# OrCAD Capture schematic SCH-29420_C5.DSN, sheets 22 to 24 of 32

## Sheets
22 P20_USB3.x_TYPE_C: size A2
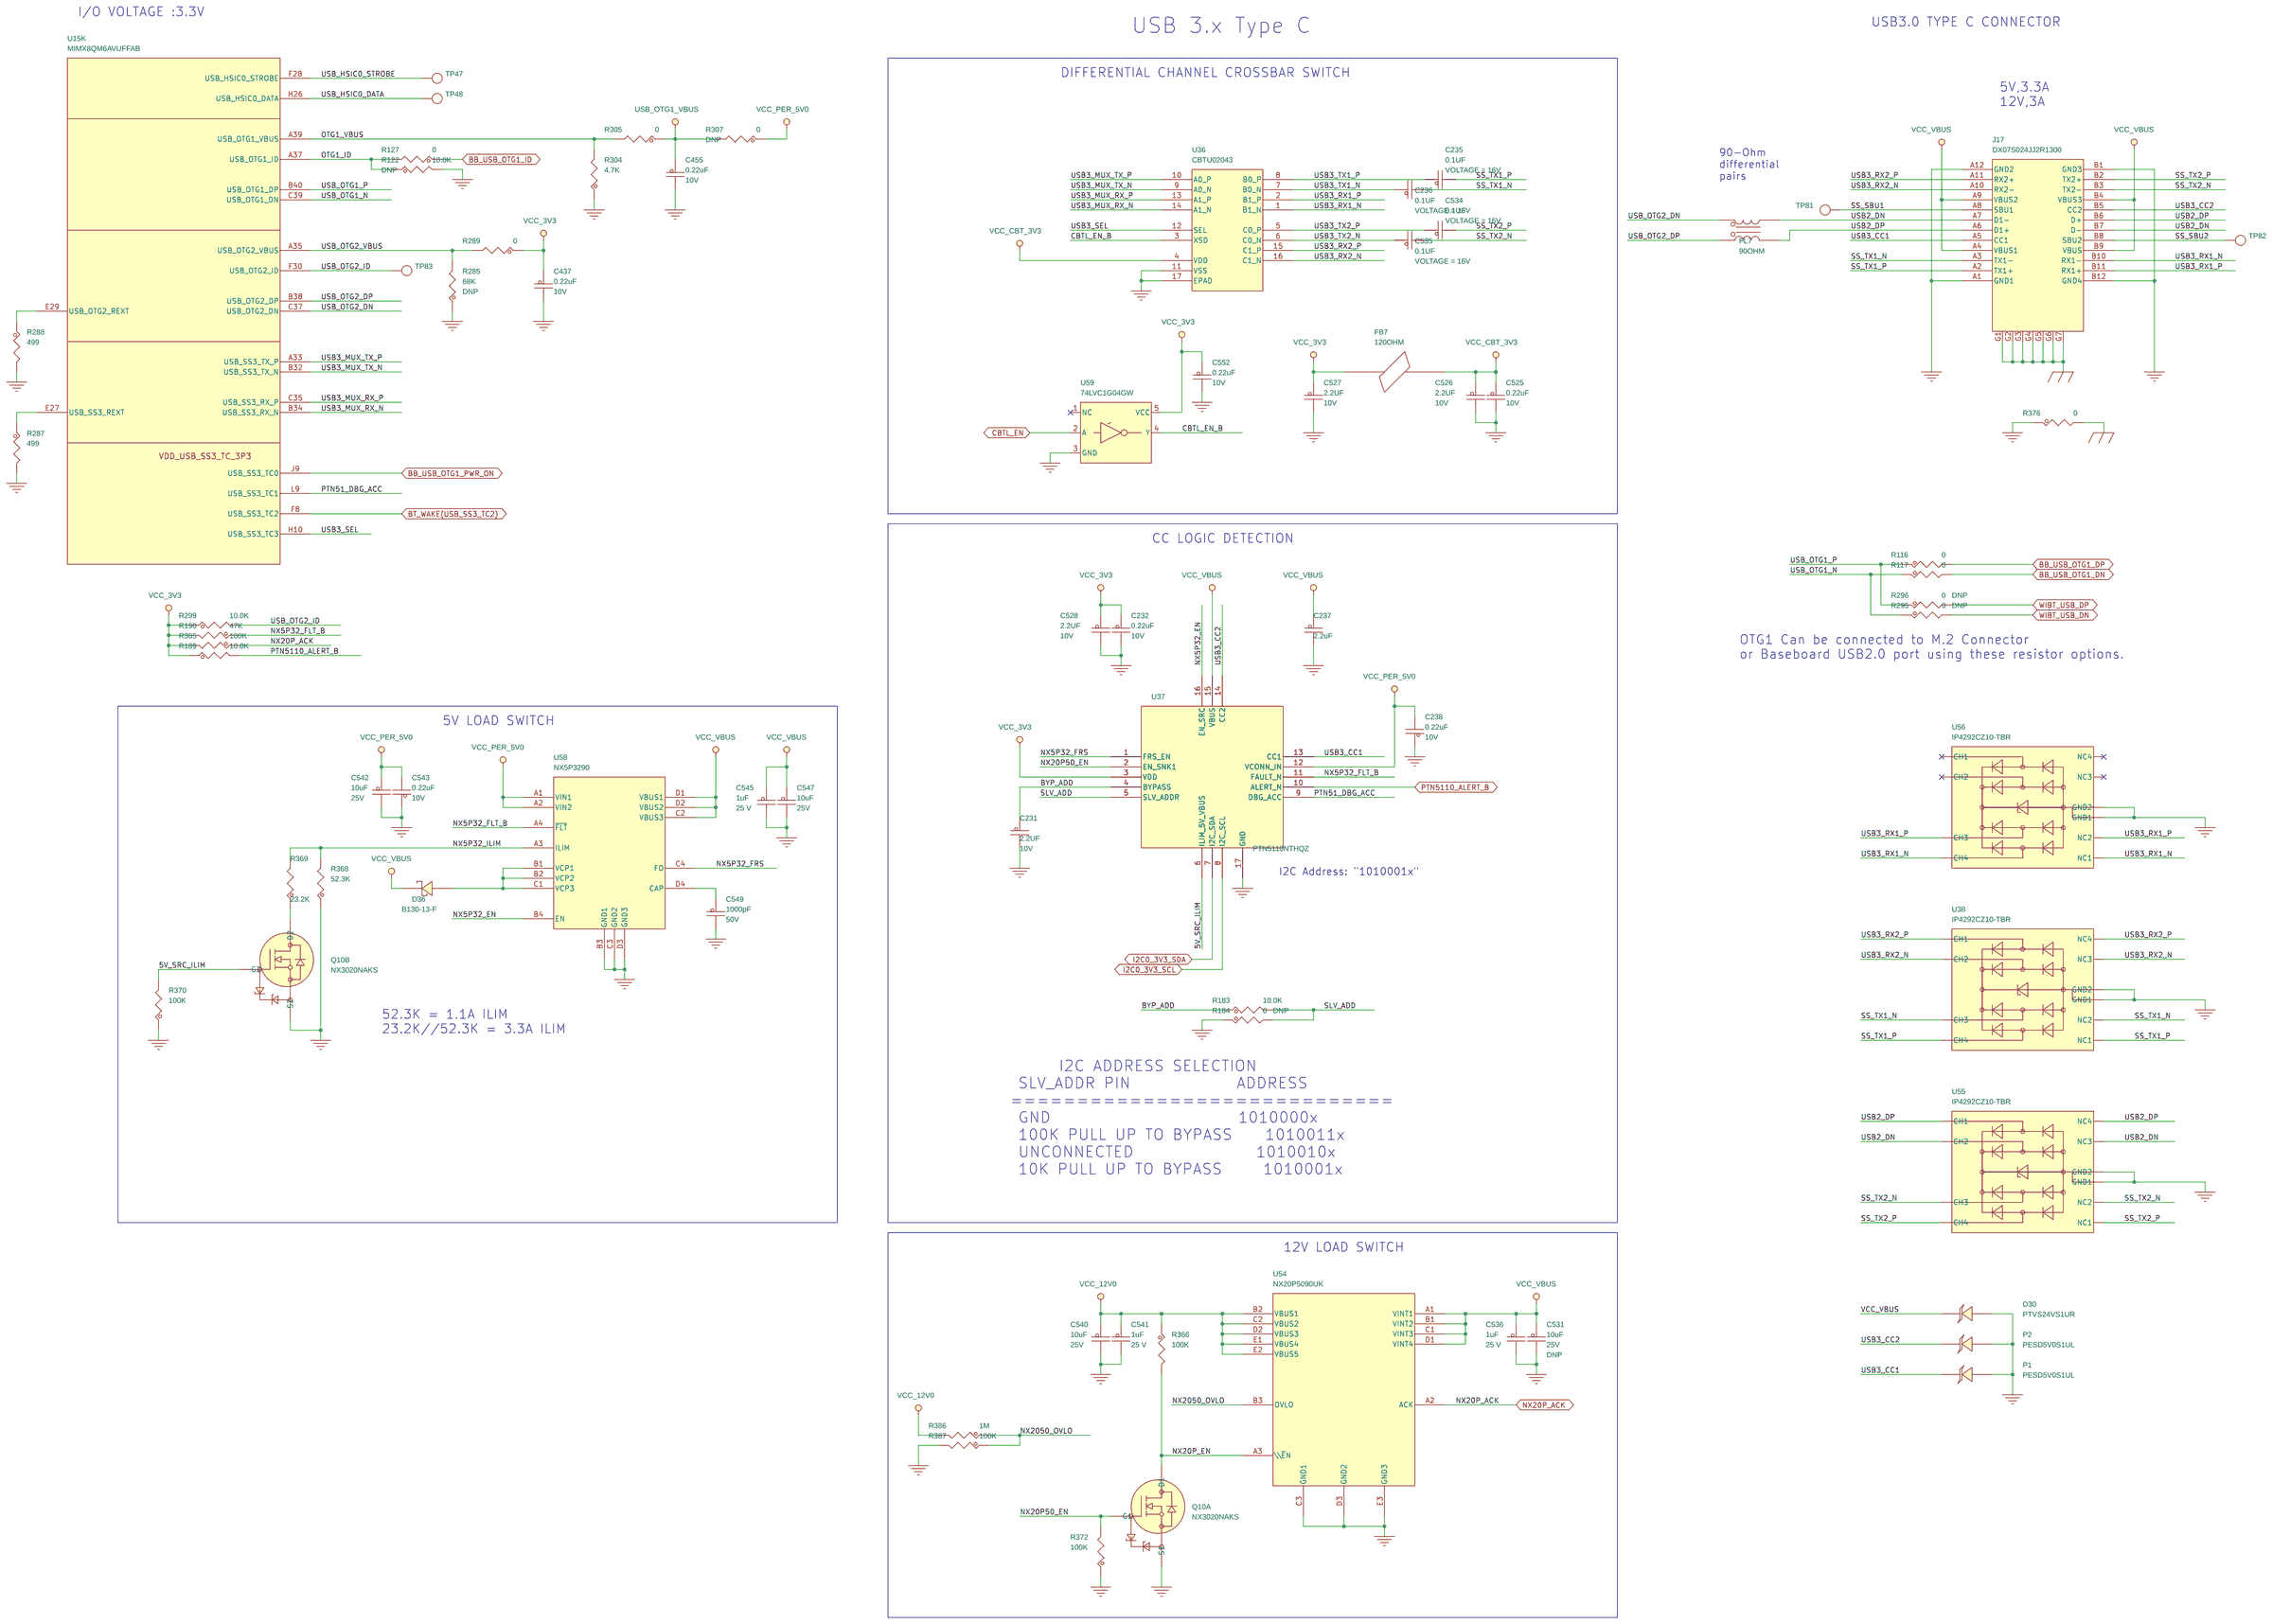
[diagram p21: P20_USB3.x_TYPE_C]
23 P21_PCIe_SATA: size A2
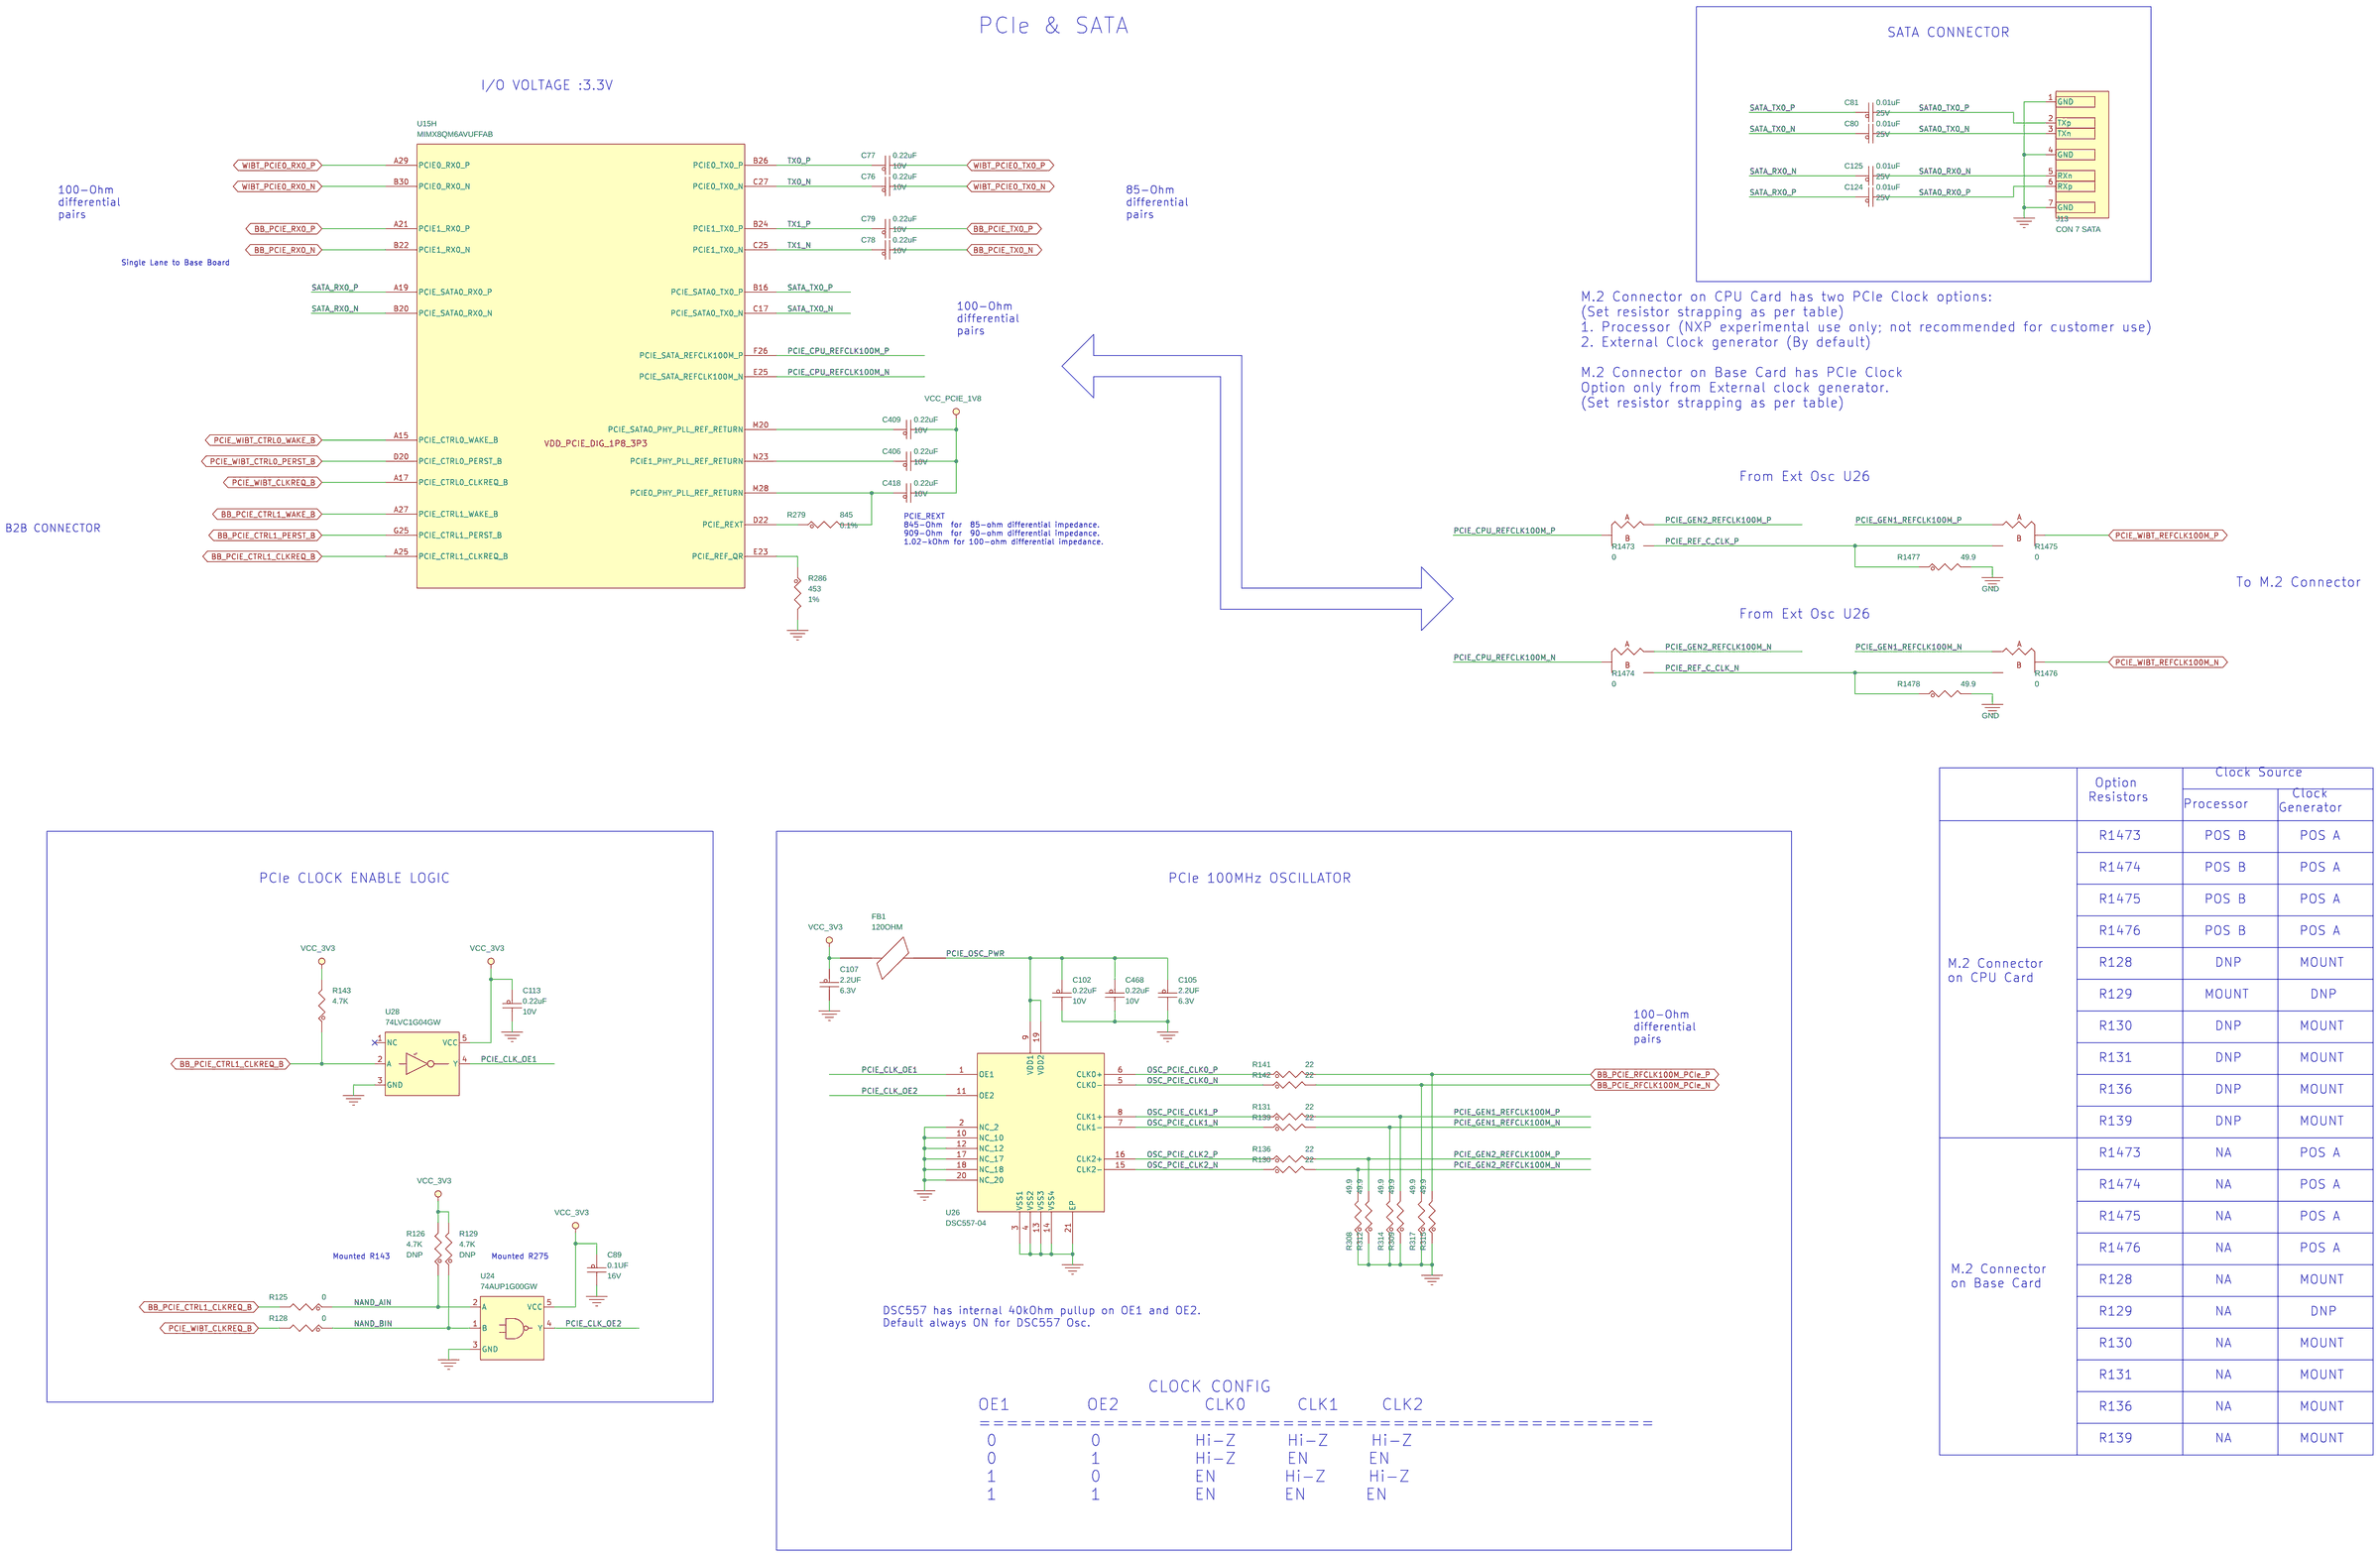
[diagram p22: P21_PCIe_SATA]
24 P23_ETHERNET_PHY: size A2

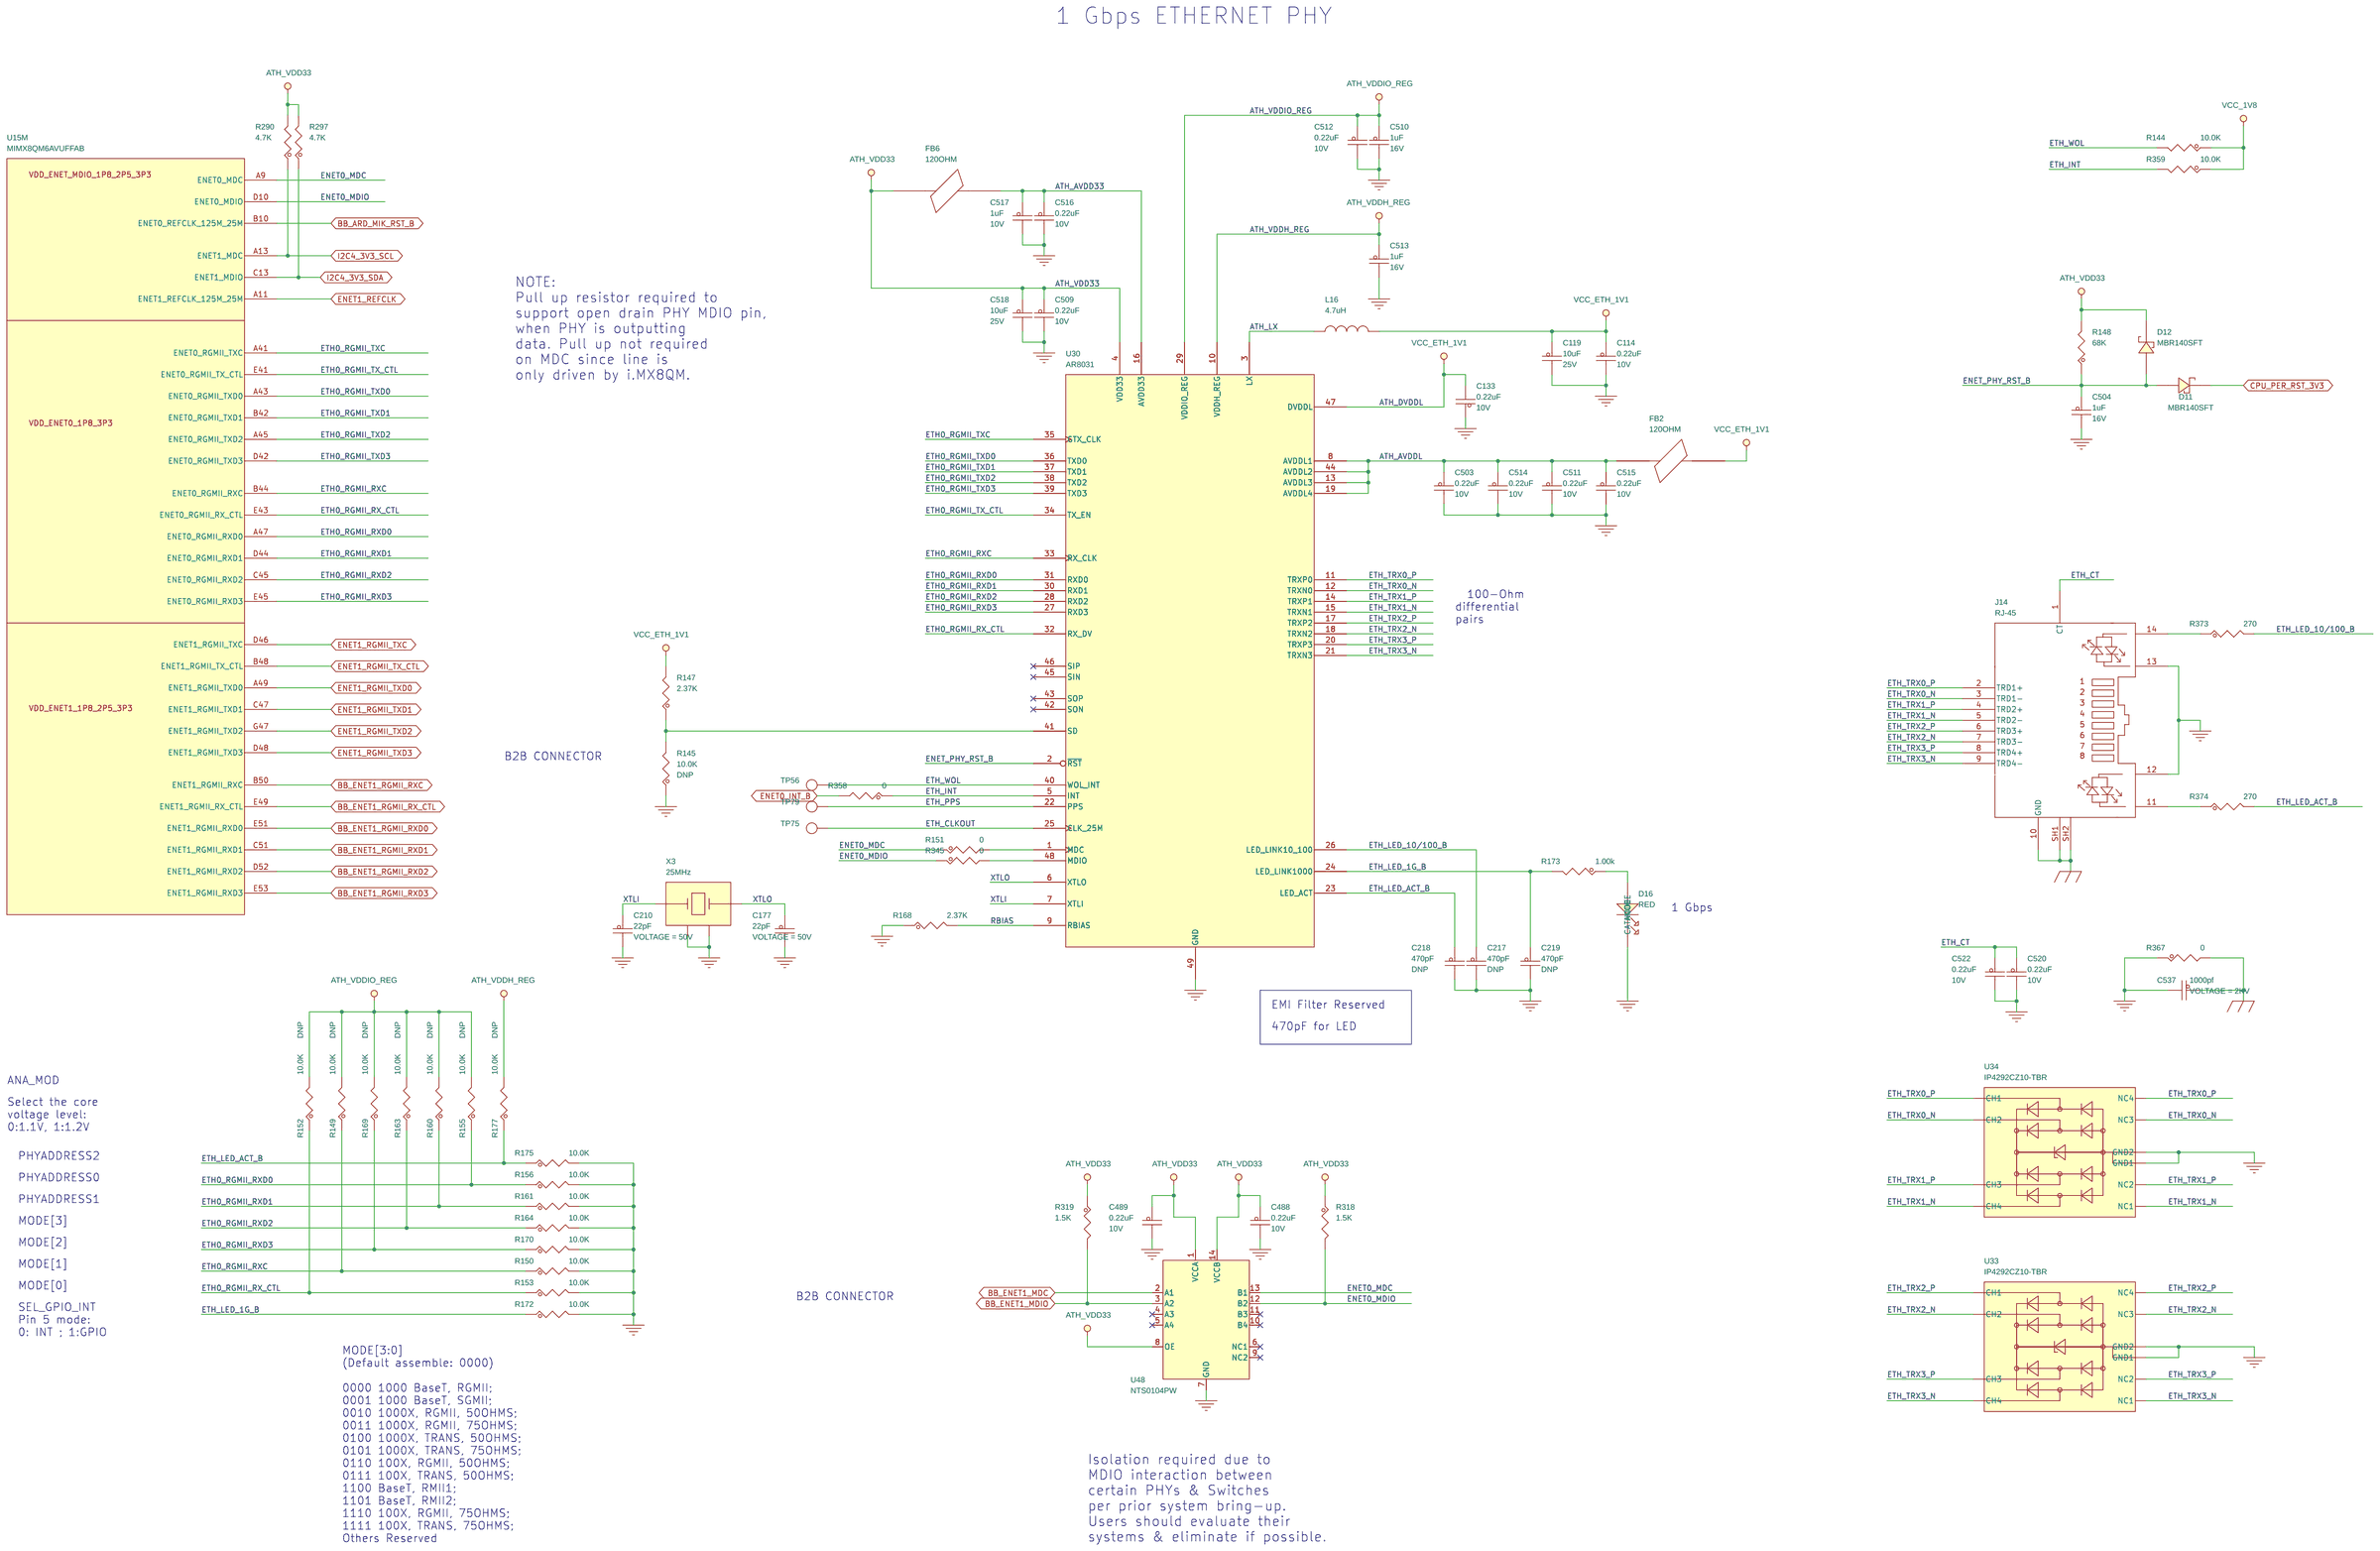
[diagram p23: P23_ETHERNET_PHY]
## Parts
sheet P20_USB3.x_TYPE_C
C231  2.2UF  [CC0402_25]
C232  0.22uF  [CC0402_25]
C235  0.1UF  [CC0402_25]
C236  0.1UF  [CC0402_25]
C237  2.2uF  [CC0603_OV]
C238  0.22uF  [CC0402_25]
C437  0.22uF  [CC0402_25]
C455  0.22uF  [CC0402_25]
C525  0.22uF  [CC0402_25]
C526  2.2UF  [CC0402_25]
C527  2.2UF  [CC0402_25]
C528  2.2UF  [CC0402_25]
C531  10uF  [CC0603_OV]
C534  0.1UF  [CC0402_25]
C535  0.1UF  [CC0402_25]
C536  1uF  [CC0402_25]
C540  10uF  [CC0603_OV]
C541  1uF  [CC0402_25]
C542  10uF  [CC0603_OV]
C543  0.22uF  [CC0402_25]
C545  1uF  [CC0402_25]
C547  10uF  [CC0603_OV]
C549  1000pF  [CC0402_25]
C552  0.22uF  [CC0402_25]
D30  PTVS24VS1UR  [sod123w]
D36  B130-13-F  [sma2_4_4p6x2p9]
FB7  120OHM  [IND_0603]
FL7  90OHM  [ind4_choke_0805]
J17  DX07S024JJ2R1300  [usb24_type_c_dx07S024_sm]
P1  PESD5V0S1UL  [sod-882]
P2  PESD5V0S1UL  [sod-882]
Q10  NX3020NAKS  [sot-363_0p65_smt]  (sections A,B)
R116  0  [RC0402_25]
R117  0  [RC0402_25]
R122  10.0K  [RC0402_25]
R127  0  [RC0402_25]
R183  10.0K  [RC0402_25]
R184  0  [RC0402_25]
R189  10.0K  [RC0402_25]
R190  47K  [RC0402_25]
R285  68K  [RC0402_25]
R287  499  [RC0402_25]
R288  499  [RC0402_25]
R289  0  [RC0402_25]
R295  0  [RC0402_25]
R296  0  [RC0402_25]
R299  10.0K  [RC0402_25]
R304  4.7K  [RC0402_25]
R305  0  [RC0402_25]
R307  0  [RC0402_25]
R365  100K  [RC0402_25]
R366  100K  [RC0402_25]
R368  52.3K  [RC0402_25]
R369  23.2K  [RC0402_25]
R370  100K  [RC0402_25]
R372  100K  [RC0402_25]
R376  0  [RC0402_25]
R386  1M  [RC0402_25]
R387  100K  [RC0402_25]
TP47  TPAD_050  [TPAD_050]
TP48  TPAD_050  [TPAD_050]
TP81  TPAD_050  [TPAD_050]
TP82  TPAD_050  [TPAD_050]
TP83  TPAD_050  [TPAD_050]
U36  CBTU02043  [huqfn16_1p6x2p4]
U37  PTN5110NTHQZ  [hx2qfn16_0p4_2p7x2p7]
U38  IP4292CZ10-TBR  [xson10_0p5_1p1x2p6mm]
U54  NX20P5090UK  [wlcsp15_0p5_1p57x2p59]
U55  IP4292CZ10-TBR  [xson10_0p5_1p1x2p6mm]
U56  IP4292CZ10-TBR  [xson10_0p5_1p1x2p6mm]
U58  NX5P3290  [bga16_0p5_2p15x2p15]
U59  74LVC1G04GW  [sc70-5]
sheet P21_PCIe_SATA
C76  0.22uF  [CC0402_25]
C77  0.22uF  [CC0402_25]
C78  0.22uF  [CC0402_25]
C79  0.22uF  [CC0402_25]
C80  0.01uF  [CC0402_25]
C81  0.01uF  [CC0402_25]
C89  0.1UF  [CC0402_25]
C102  0.22uF  [CC0402_25]
C105  2.2UF  [CC0402_25]
C107  2.2UF  [CC0402_25]
C113  0.22uF  [CC0402_25]
C124  0.01uF  [CC0402_25]
C125  0.01uF  [CC0402_25]
C406  0.22uF  [0402_CC]
C409  0.22uF  [CC0402_25]
C418  0.22uF  [CC0402_25]
C468  0.22uF  [CC0402_25]
FB1  120OHM  [IND_0603]
J13  CON 7 SATA  [con7_sata_th_17x5mm]
R125  0  [RC0402_25]
R126  4.7K  [RC0402_25]
R128  0  [RC0402_25]
R129  4.7K  [RC0402_25]
R130  22  [RC0402_25]
R131  22  [RC0402_25]
R136  22  [RC0402_25]
R139  22  [RC0402_25]
R141  22  [RC0402_25]
R142  22  [RC0402_25]
R143  4.7K  [RC0402_25]
R279  845  [RC0402_25]
R286  453  [RC0402_25]
R308  49.9  [RC0402_25]
R309  49.9  [RC0402_25]
R312  49.9  [RC0402_25]
R314  49.9  [RC0402_25]
R315  49.9  [RC0402_25]
R317  49.9  [RC0402_25]
R1473  0  [RC0402_X2]
R1474  0  [RC0402_X2]
R1475  0  [RC0402_X2]
R1476  0  [RC0402_X2]
R1477  49.9  [RC0402_25]
R1478  49.9  [RC0402_25]
U24  74AUP1G00GW  [sc70-5]
U26  DSC557-04  [qfn20_0p5_5x3mm_ep3p9x2p1]
U28  74LVC1G04GW  [sc70-5]
sheet P23_ETHERNET_PHY
C114  0.22uF  [CC0402_25]
C119  10uF  [CC0603_OV]
C133  0.22uF  [CC0402_25]
C177  22pF  [CC0402_25]
C210  22pF  [CC0402_25]
C217  470pF  [CC0402_25]
C218  470pF  [CC0402_25]
C219  470pF  [CC0402_25]
C488  0.22uF  [CC0402_25]
C489  0.22uF  [CC0402_25]
C503  0.22uF  [CC0402_25]
C504  1uF  [CC0402_25]
C509  0.22uF  [CC0402_25]
C510  1uF  [CC0402_25]
C511  0.22uF  [CC0402_25]
C512  0.22uF  [CC0402_25]
C513  1uF  [CC0402_25]
C514  0.22uF  [CC0402_25]
C515  0.22uF  [CC0402_25]
C516  0.22uF  [CC0402_25]
C517  1uF  [CC0402_25]
C518  10uF  [CC0603_OV]
C520  0.22uF  [CC0402_25]
C522  0.22uF  [CC0402_25]
C537  1000pf  [CC1210]
D11  MBR140SFT  [sod123lf]
D12  MBR140SFT  [sod123lf]
D16  RED  [LED_0603]
FB2  120OHM  [IND_0603]
FB6  120OHM  [IND_0603]
J14  RJ-45  [con_rj45_10_2led_th]
L16  4.7uH  [ind_nr4018_4x4]
R144  10.0K  [RC0402_25]
R145  10.0K  [RC0402_25]
R147  2.37K  [RC0402_25]
R148  68K  [RC0402_25]
R149  10.0K  [RC0402_25]
R150  10.0K  [RC0402_25]
R151  0  [RC0402_25]
R152  10.0K  [RC0402_25]
R153  10.0K  [RC0402_25]
R155  10.0K  [RC0402_25]
R156  10.0K  [RC0402_25]
R160  10.0K  [RC0402_25]
R161  10.0K  [RC0402_25]
R163  10.0K  [RC0402_25]
R164  10.0K  [RC0402_25]
R168  2.37K  [RC0402_25]
R169  10.0K  [RC0402_25]
R170  10.0K  [RC0402_25]
R172  10.0K  [RC0402_25]
R173  1.00k  [RC0402_25]
R175  10.0K  [RC0402_25]
R177  10.0K  [RC0402_25]
R290  4.7K  [RC0402_25]
R297  4.7K  [RC0402_25]
R318  1.5K  [RC0402_25]
R319  1.5K  [RC0402_25]
R345  0  [RC0402_25]
R358  0  [RC0402_25]
R359  10.0K  [RC0402_25]
R367  0  [RC0402_25]
R373  270  [RC0402_25]
R374  270  [RC0402_25]
TP56  TPAD_050  [TPAD_050]
TP75  TPAD_050  [TPAD_050]
TP79  TPAD_050  [TPAD_050]
U15  MIMX8QM6AVUFFAB  [imx8_bga_1313]  (sections A,B,C,D,E,F,G,H,I,J,K,L,M,N,O,P,Q,R,S,T,U)
U30  AR8031  [qfn48_0p4_6x6mm_epad]
U33  IP4292CZ10-TBR  [xson10_0p5_1p1x2p6mm]
U34  IP4292CZ10-TBR  [xson10_0p5_1p1x2p6mm]
U48  NTS0104PW  [tssop14]
X3  25MHz  [xtal4_5p2x3p4mm_sm]

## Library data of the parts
C231 C526-C528 = CAP_NP: CAP CER 2.2UF 10V 10% X5R 0402; AGILE_PN: 150-79475; CAD_APPROVED: Yes; EN: 102-1-00208; FPLIST: CC0402_25,CC0402_HD,0402_CC; HEIGHT: 0.56MM; MFG_NAME01: AVX; MFG_PN01: 0402ZD225KAT2A; ROHS: Yes; TOL: 10%; Tolerance: 10%; VOLTAGE: 10V
C76-C79 C102 C113 C114 C133 C232 C238 C406 C409 C418 C437 C455 C468 C488 C489 C503 C509 C511 C512 C514-C516 C520 C522 C525 C543 C552 = CAP_NP: CAP CER 0.22uF 10V 10% X7R AEC-Q200 0402; AGILE_PN: 150-79031; CAD_APPROVED: Yes; EN: 102-1-01816; FPLIST: CC0402_25,CC0402_HD,0402_CC; HEIGHT: 0.55MM; MFG_NAME01: TDK; MFG_PN01: CGA2B1X7R1A224K050BC; ROHS: Yes; TOL: 10%; Tolerance: 10%; VOLTAGE: 10V
C89 C235 C236 C534 C535 = CAP_NP: CAP CER 0.1UF 16V 10% X7R 0402; AGILE_PN: 150-75182; CAD_APPROVED: Yes; EN: 102-1-01629; FPLIST: CC0402_25,CC0402_HD,0402_CC; HEIGHT: 0.635MM; MFG_NAME01: AVX; MFG_PN01: 0402YC104KAT2A; ROHS: Yes; TOL: 10%; Tolerance: 10%; VOLTAGE: 16V
C237 = CAP_NP: CAP CER 2.2uF 50V 10% X5R 0603; AGILE_PN: 150-79973; CAD_APPROVED: Yes; EN: 102-1-02211; FPLIST: CC0603_OV,CC0603,0603_CC; HEIGHT: 1MM; MFG_NAME01: Taiyo Yuden; MFG_PN01: UMK107BBJ225KA-T; ROHS: Yes; TOL: 10%; Temp_Range: -55 to 85&#8451;; Tolerance: 10%; VOLTAGE: 150V
C531 = CAP_NP: CAP CER 10uF 25V 20% X5R 0603; AGILE_PN: 150-79272; ASSY_OPT: DNP; CAD_APPROVED: Yes; EN: 102-1-01982; FPLIST: CC0603_OV,CC0603,0603_CC; HEIGHT: 1MM; MFG_NAME01: Murata; MFG_PN01: GRM188R61E106MA73D; ROHS: Yes; TOL: 20%; Tolerance: 20%; VOLTAGE: 25V
C536 C541 C545 = CAP_NP: CAP CER 1uF 25V 10% X5R 0402; AGILE_PN: 150-80001; CAD_APPROVED: Yes; EN: 102-1-01993; FPLIST: CC0402_25,CC0402_HD,0402_CC; HEIGHT: 0.55MM; MFG_NAME01: MURATA; MFG_PN01: GRM155R61E105KA12; ROHS: Yes; TOL: 10%; Temp_Range: -55°C to +85°C; Tolerance: 10%; VOLTAGE: 25 V
C119 C518 C540 C542 = CAP_NP: CAP CER 10uF 25V 20% X5R 0603; AGILE_PN: 150-79272; CAD_APPROVED: Yes; EN: 102-1-01982; FPLIST: CC0603_OV,CC0603,0603_CC; HEIGHT: 1MM; MFG_NAME01: Murata; MFG_PN01: GRM188R61E106MA73D; ROHS: Yes; TOL: 20%; Tolerance: 20%; VOLTAGE: 25V
C547 = CAP_NP: CAP CER 10uF 25V 20% X5R 0603; AGILE_PN: 150-79272; ASSY_OPT: NM; CAD_APPROVED: Yes; EN: 102-1-01982; FPLIST: CC0603_OV,CC0603,0603_CC; HEIGHT: 1MM; MFG_NAME01: Murata; MFG_PN01: GRM188R61E106MA73D; ROHS: Yes; TOL: 20%; Tolerance: 20%; VOLTAGE: 25V
C549 = CAP_NP: CAP CER 1000PF 50V X7R 5% 0402; AGILE_PN: 150-75774; CAD_APPROVED: Yes; EN: 102-1-00054; FPLIST: CC0402_25,CC0402_HD,0402_CC; HEIGHT: 0.6MM; MFG_NAME01: CAPAX TECHNOLOGIES INC.; MFG_PN01: 0402X102J500SNT; ROHS: Yes; TOL: 5%; Tolerance: 5%; VOLTAGE: 50V
D30 = DIODE_TVS: DIODE TVS 400W 24V AEC-Q101 SOD123W; AGILE_PN: 480-79613; CAD_APPROVED: Yes; EN: 305-1-00269; HEIGHT: 1.1MM; MFG_NAME01: NEXPERIA; MFG_PN01: PTVS24VS1UR,115; ROHS: Yes
D36 = DIODE_SCHTKY: DIODE SCH RECT 1A 30V SMA; AGILE_PN: 480-79846; CAD_APPROVED: Yes; EN: 106-2-00016; HEIGHT: 2.5MM; MFG_NAME01: Diodes Inc; ROHS: Yes; Temp_Range: -65C to 150C
FB1 FB2 FB6 FB7 = BEAD_FERRITE: IND FER BEAD 120OHM@100MHZ 2A 25% 0603; AGILE_PN: 180-30008; CAD_APPROVED: Yes; EN: 104-1-00022; FPLIST: IND_0603,0603_CC; HEIGHT: 0.95MM; MFG_NAME01: MURATA; MFG_PN01: BLM18PG121SH1; PART_TYPE: FERRITE; ROHS: Yes; TOL: 25%; Tolerance: 25%
FL7 = DLW43: IND CHK 90 OHM@100MHZ 330MA 25% 0805; AGILE_PN: 180-76336; CAD_APPROVED: Yes; EN: 303-0-00024; HEIGHT: 1MM; MFG_NAME01: MURATA; MFG_PN01: DLW21HN900SQ2L; PART_TYPE: CHOKE; ROHS: Yes; TOL: 25%; Tolerance: 25%
J17 = USB_24_TYPE_C: CON 24 USB TYPE_C RA SHLD SMT 0.5MM SP 130H AU; AGILE_PN: 211-79865; CAD_APPROVED: Yes; EN: 201-2-00583; HEIGHT: 3.3MM; MFG_NAME01: JAE; ROHS: Yes
P1 P2 = DIODE_TVS: DIODE TVS UNIDIR 5V AEC-Q101 SOD882; AGILE_PN: 480-79614; CAD_APPROVED: Yes; EN: 305-1-00268; HEIGHT: 0.5MM; MFG_NAME01: NEXPERIA; MFG_PN01: PESD5V0S1UL,315; ROHS: Yes
Q10 = TRAN_DUAL_NMOS_BSS138: TRAN NMOS SW DUAL 180MA 30V 4.5 OHM SOT363; AGILE_PN: 480-79692; CAD_APPROVED: Yes; EN: 107-2-00207; HEIGHT: 1.1 MM; MFG_NAME01: NEXPERIA; MFG_PN01: NX3020NAKS,115; ROHS: Yes
R116 R117 R125 R127 R128 R151 R289 R305 R345 R358 R367 R376 = RES: RES MF ZERO OHM 1/16W -- AEC-Q200 0402; AGILE_PN: 470-80742; CAD_APPROVED: Yes; EN: 101-1-00001; FPLIST: RC0402_25,RC0402_HD,0402_CC; HEIGHT: 0.45 MM; MFG_NAME01: VISHAY INTERTECHNOLOGY; MFG_PN01: CRCW04020000Z0ED; ROHS: Yes
R122 R145 R149 R152 R155 R160 R163 R169 R177 = RES: RES MF 10.0K 1/16W 1% 0402; AGILE_PN: 470-80574; ASSY_OPT: DNP; CAD_APPROVED: Yes; EN: 101-1-00389; FPLIST: RC0402_25,RC0402_HD,0402_CC; HEIGHT: 0.4MM; MFG_NAME01: WALSIN TECHNOLOGY CORP.; MFG_PN01: WR04X1002FTL; ROHS: Yes; TOL: 1%; Tolerance: 1%
R144 R150 R153 R156 R161 R164 R170 R172 R175 R183 R189 R299 R359 = RES: RES MF 10.0K 1/16W 1% 0402; AGILE_PN: 470-80574; CAD_APPROVED: Yes; EN: 101-1-00389; FPLIST: RC0402_25,RC0402_HD,0402_CC; HEIGHT: 0.4MM; MFG_NAME01: WALSIN TECHNOLOGY CORP.; MFG_PN01: WR04X1002FTL; ROHS: Yes; TOL: 1%; Tolerance: 1%
R184 R295 R296 R307 = RES: RES MF ZERO OHM 1/16W -- AEC-Q200 0402; AGILE_PN: 470-80742; ASSY_OPT: DNP; CAD_APPROVED: Yes; EN: 101-1-00001; FPLIST: RC0402_25,RC0402_HD,0402_CC; HEIGHT: 0.45 MM; MFG_NAME01: VISHAY INTERTECHNOLOGY; MFG_PN01: CRCW04020000Z0ED; ROHS: Yes
R190 = RES: RES MF 47K 1/10W 1% AEC-Q200 0402; AGILE_PN: 470-81731; CAD_APPROVED: Yes; EN: 101-1-03402; FPLIST: RC0402_25,RC0402_HD,0402_CC; HEIGHT: 0.40 MM; MFG_NAME01: KOA SPEER; MFG_PN01: RK73H1ETTP4702F; ROHS: Yes; TOL: 1%; Temp_Range: -55C to +155C; Tolerance: 1%
R285 = RES: RES MF 68K 1/16W 5% 0402; AGILE_PN: 470-30330; ASSY_OPT: DNP; CAD_APPROVED: Yes; EN: 101-1-02813; FPLIST: RC0402_25,RC0402_HD,0402_CC; HEIGHT: 0.4MM; MFG_NAME01: TYCO ELECTRONICS; MFG_PN01: CRG0402J68K; ROHS: Yes; TOL: 5%; Tolerance: 5%
R287 R288 = RES: RES MF 499 OHM 1/16W 1% 0402; AGILE_PN: 470-30807; CAD_APPROVED: Yes; EN: 101-1-00264; FPLIST: RC0402_25,RC0402_HD,0402_CC; HEIGHT: 0.40 MM; MFG_NAME01: ROHM; MFG_PN01: MCR01MZPF4990; ROHS: Yes; TOL: 1%; Tolerance: 1%
R143 R290 R297 R304 = RES: RES MF 4.7K 1/16W 5% 0402; AGILE_PN: 470-75626; CAD_APPROVED: Yes; EN: 101-1-02785; FPLIST: RC0402_25,RC0402_HD,0402_CC,RC0402_X2; HEIGHT: 0.41mm; MFG_NAME01: NIC COMPONENTS CORP; MFG_PN01: NRCL04J472TRF; ROHS: Yes; TOL: 5%; Tolerance: 5%
R365 R366 R370 R372 R387 = RES: RES MF 100K 1/16W 5% 0402; AGILE_PN: 470-75597; CAD_APPROVED: Yes; EN: 101-1-02817; FPLIST: RC0402_25,RC0402_HD,0402_CC; HEIGHT: 0.40 MM; MFG_NAME01: VENKEL COMPANY; MFG_PN01: CR0402-16W-104JT; ROHS: Yes; TOL: 5%; Tolerance: 5%
R368 = RES: RES MF 52.3K 1/10W 1% AEC-Q200 0402; AGILE_PN: 470-81734; CAD_APPROVED: Yes; EN: 101-1-00458; FPLIST: RC0402_25,RC0402_HD,0402_CC; HEIGHT: 0.40 MM; MFG_NAME01: KOA SPEER; MFG_PN01: RK73H1ETTP5232F; ROHS: Yes; TOL: 1%; Temp_Range: -55C to +155C; Tolerance: 1%
R369 = RES: RES MF 23.2K 1/10W 1% AEC-Q200 0402; AGILE_PN: 470-30986; CAD_APPROVED: Yes; EN: 101-1-03903; FPLIST: RC0402_25,RC0402_HD,0402_CC; HEIGHT: 0.40 MM; MFG_NAME01: KOA SPEER; MFG_PN01: RK73H1ETTP2322F; ROHS: Yes; Temp_Range: -55C to +155C; Tolerance: 1%
R386 = RES: RES MF 1M 1/16W 1% 0402; AGILE_PN: 470-80575; CAD_APPROVED: Yes; EN: 101-1-00581; FPLIST: RC0402_25,RC0402_HD,0402_CC; HEIGHT: 0.4MM; MFG_NAME01: BOURNS; MFG_PN01: CR0402-FX-1004GLF; ROHS: Yes; TOL: 1%; Tolerance: 1%
TP47 TP48 TP56 TP75 TP79 TP81-TP83 = TESTLOOP: TEST POINT PAD 50MIL DIA SMT, NO PART TO ORDER; AGILE_PN: 211-76644; CAD_APPROVED: Yes; HEIGHT: 0.1MM; MFG_NAME01: NOTACOMPONENT; MFG_PN01: NOTACOMPONENT; ROHS: Yes
U36 = CBTU02043HEJ_17P: IC DIFF MUX/DEMUX 2:1 1.62-3.63V HUQFN16; AGILE_PN: TMP-WF-29679; CAD_APPROVED: Yes; EN: 301-0-01905; HEIGHT: 0.55MM; MFG_NAME01: NXP SEMICONDUCTORS; MFG_PN01: CBTU02043HEJ; PRE_APN: 312-81720; ROHS: Yes
U37 = PTN5110_16P_EP: IC USB PD PHY 1PORT 2.7-5.5V HX2QFN16; AGILE_PN: 315-82772; CAD_APPROVED: YES; EN: 301-0-03045; HEIGHT: 0.4 MM; MFG_NAME01: NXP Semiconductors; ROHS: YES; Temp Range: -40  °C - 85 °C; VOLTAGE: 2.7-5.5V
U33 U34 U38 U55 U56 = PUSB3F96_DFN2510A_10P: DIODE ESD TVS ARRAY USB2 USB3 5.5V 4A DFN2510A-10; AGILE_PN: 480-79837; CAD_APPROVED: Yes; EN: 301-0-01726; HEIGHT: 0.5MM; MFG_NAME01: NEXPERIA; MFG_PN01: IP4292CZ10-TBR,115; ROHS: Yes; Temp_Range: -40C to +85C
U54 = NX20P5090UK: IC USB PWR SW 5A 2.5-20V WLCSP15; AGILE_PN: 315-81116; CAD_APPROVED: Yes; EN: 301-0-01659; HEIGHT: 0.595MM; MFG_NAME01: NXP SEMICONDUCTORS; MFG_PN01: NX20P5090UKAZ; ROHS: Yes
U58 = NX5P3290_16P: IC USB PD SWITCH 4-5.5V WLCSP16; AGILE_PN: 315-81121; CAD_APPROVED: Yes; EN: 301-0-01656; HEIGHT: 0.595MM; MFG_NAME01: NXP SEMICONDUCTORS; MFG_PN01: NX5P3290UKZ; ROHS: Yes
U28 U59 = NC7SZ14: IC INV SGL 1.65-5.5V TSSOP5; AGILE_PN: 315-81077; CAD_APPROVED: Yes; EN: 301-0-01255; HEIGHT: 1.1MM; MFG_NAME01: NEXPERIA; MFG_PN01: 74LVC1G04GW,125; ROHS: Yes
C80 C81 C124 C125 = CAP_NP: CAP CER 0.01UF 25V 10% X7R 0402; AGILE_PN: 150-75183; CAD_APPROVED: Yes; EN: 102-1-00027; FPLIST: CC0402_25,CC0402_HD,0402_CC; HEIGHT: 0.635mm; MFG_NAME01: AVX; MFG_PN01: 04023C103KAT2A; ROHS: Yes; TOL: 10%; Tolerance: 10%; VOLTAGE: 25V
C105 C107 = CAP_NP: CAP CER 2.2UF 6.3V 20% X5R 0402; AGILE_PN: 150-76792; CAD_APPROVED: Yes; EN: 102-1-01843; FPLIST: CC0402_25,CC0402_HD,0402_CC; HEIGHT: 0.55MM; MFG_NAME01: KEMET; MFG_PN01: C0402C225M9PACTU; ROHS: Yes; TOL: 20%; Tolerance: 20%; VOLTAGE: 6.3V
J13 = SATA_PLUG7: CON 1X7 PLUG SATA TH 50MIL SP 335H -- 96L; AGILE_PN: 210-79711; CAD_APPROVED: Yes; EN: 201-1-00982; HEIGHT: 8.527 MM; MFG_NAME01: 3M; MFG_PN01: 5607-5102-SH; ROHS: Yes
R126 R129 = RES: RES MF 4.7K 1/16W 5% 0402; AGILE_PN: 470-75626; ASSY_OPT: DNP; CAD_APPROVED: Yes; EN: 101-1-02785; FPLIST: RC0402_25,RC0402_HD,0402_CC,RC0402_X2; HEIGHT: 0.41mm; MFG_NAME01: NIC COMPONENTS CORP; MFG_PN01: NRCL04J472TRF; ROHS: Yes; TOL: 5%; Tolerance: 5%
R130 R131 R136 R139 R141 R142 = RES: RES MF 22 OHM 1/16W 5% 0402; AGILE_PN: 470-75605; CAD_APPROVED: Yes; EN: 101-1-03406; FPLIST: RC0402_25,RC0402_HD,0402_CC; HEIGHT: 0.4MM; MFG_NAME01: BOURNS; MFG_PN01: CR0402-JW-220GLF; ROHS: Yes; TOL: 5%; Tolerance: 5%
R279 = RES: RES MF 845 OHM 1/16W 0.1% 0402; AGILE_PN: 470-81874; CAD_APPROVED: Yes; EN: 101-1-04012; FPLIST: RC0402_25,RC0402_HD,0402_CC; HEIGHT: 0.35MM; MFG_NAME01: Yageo; MFG_PN01: RT0402BRD07845RL; ROHS: Yes; TOL: 0.1%; Temp_Range: -55C to +155C; Tolerance: 0.1%
R286 = RES: RES MF 453 OHM 1/16W 1% 0402; AGILE_PN: 470-30804; CAD_APPROVED: Yes; EN: 101-1-00260; FPLIST: RC0402_25,RC0402_HD,0402_CC; HEIGHT: 0.40 MM; MFG_NAME01: YAGEO AMERICA; MFG_PN01: RC0402FR-07453RL; ROHS: Yes; TOL: 1%; Tolerance: 1%
R308 R309 R312 R314 R315 R317 = RES: RES MF 49.9 OHM 1/16W 1% 0402; AGILE_PN: 470-75360; CAD_APPROVED: Yes; EN: 101-1-00168; FPLIST: RC0402_25,RC0402_HD,0402_CC; HEIGHT: 0.4MM; MFG_NAME01: BOURNS; MFG_PN01: CR0402-FX-49R9GLF; ROHS: Yes; TOL: 1%; Tolerance: 1%
R1473-R1476 = RES_3PIN: RES MF ZERO OHM 1/16W 5% 0402; AGILE_PN: 470-75394; CAD_APPROVED: Yes; EN: 101-1-04000; FPLIST: RC0402_25,RC0402_HD,RC0402_X2,0402_CC; HEIGHT: 0.45 MM; MFG_NAME01: ROHM; MFG_PN01: MCR01MZPJ000; ROHS: Yes; TOL: 5%; Tolerance: 5%
R1477 R1478 = RES: RES MF 49.9 OHM 1/16W 1% 0402; AGILE_PN: 470-75360; CAD_APPROVED: Yes; EN: 101-1-00168; FPLIST: RC0402_25,RC0402_HD,0402_CC; HEIGHT: 0.4MM; MFG_NAME01: BOURNS; MFG_PN01: CR0402-FX-49R9GLF; ROHS: Yes; TOL: 1%
U24 = 74AUP1G00GW: IC GATE NAND 2IN 0.8-3.6V.TSSOP5; AGILE_PN: 312-81222; CAD_APPROVED: Yes; EN: 301-0-01730; HEIGHT: 1.1MM; MFG_NAME01: NEXPERIA; MFG_PN01: 74AUP1G00GW,125; ROHS: Yes
U26 = DSC557_QFN20_EP: IC PCIe CLK GEN 100MHZ 2.25-3.6V QFN20; AGILE_PN: 312-81849; CAD_APPROVED: Yes; EN: 301-0-01848; HEIGHT: 0.9MM; MFG_NAME01: MICROCHIP TECHNOLOGY INC; MFG_PN01: DSC557-04444KI1; ROHS: Yes
C177 C210 = CAP_NP: CAP CER 22pF 50V 1% C0G 0402; AGILE_PN: 150-79491; CAD_APPROVED: Yes; EN: 102-1-00765; FPLIST: CC0402_25,CC0402_HD,0402_CC; HEIGHT: 0.56MM; MFG_NAME01: AVX; MFG_PN01: 04025A220FAT2A; ROHS: Yes; TOL: 1%; Tolerance: 1%; VOLTAGE: 50V
C217-C219 = CAP_NP: CAP CER 470pF 50V 10% X7R AEC-Q200 0402; AGILE_PN: 150-79233; ASSY_OPT: DNP; CAD_APPROVED: Yes; EN: 102-1-00071; FPLIST: CC0402_25,CC0402_HD,0402_CC; HEIGHT: 0.55MM; MFG_NAME01: Murata; MFG_PN01: GCM155R71H471KA37; ROHS: Yes; TOL: 10%; Tolerance: 10%
C504 C510 C513 = CAP_NP: CAP CER 1uF 16V 10% X5R 0402; AGILE_PN: 150-79794; CAD_APPROVED: Yes; EN: 102-1-01641; FPLIST: CC0402_25,CC0402_HD,0402_CC; HEIGHT: 0.55MM; MFG_NAME01: NIC COMPONENTS CORP; MFG_PN01: NMC0402X5R105K16TRPF; ROHS: Yes; TOL: +/-10%; Tolerance: +/-10%; VOLTAGE: 16V
C517 = CAP_NP: CAP CER 1uF 10V 10% X7S AEC-Q200 0402; AGILE_PN: 150-79497; CAD_APPROVED: Yes; EN: 102-1-02280; FPLIST: CC0402_25,CC0402_HD,0402_CC; HEIGHT: 0.7MM; MFG_NAME01: murata; MFG_PN01: GCM155C71A105KE38D; ROHS: Yes; TOL: 10%; Tolerance: 10%; VOLTAGE: 10V
C537 = CAP_NP: CAP CER 1000PF 2KV 10% X7R 1210; AGILE_PN: 150-75027; CAD_APPROVED: Yes; EN: 102-1-01612; FPLIST: CC1210,1210_CC; HEIGHT: 1.7MM; MFG_NAME01: AVX; MFG_PN01: 1210GC102KAT1A; ROHS: Yes; TOL: 10%; Tolerance: 10%; VOLTAGE: 2KV
D11 D12 = DIODE_SCHTKY: DIODE SCH PWR RECT 1A 40V SOD123; AGILE_PN: 480-30006; CAD_APPROVED: Yes; EN: 106-2-00107; FPLIST: sod123lf,SOD123; HEIGHT: 1.0 MM; MFG_NAME01: ON SEMICONDUCTOR; MFG_PN01: MBR140SFT1G; ROHS: Yes
D16 = LED: LED RED SGL 20MA 0603; AGILE_PN: 370-76632; CAD_APPROVED: Yes; EN: 106-4-00247; HEIGHT: 0.45MM; MFG_NAME01: LITE ON; MFG_PN01: LTST-C193KRKT-5A; ROHS: Yes
J14 = RJ45_2_DUAL_LED_10P: CON 2X5 RJ-45 DUAL-LED SHLD RA TH 1.27MM SP 549H AU 120L; AGILE_PN: 210-81462; CAD_APPROVED: Yes; EN: 201-2-00061; HEIGHT: 13.95MM; MFG_NAME01: WURTH ELEKTRONIK EISOS GMBH & CO. KG; MFG_PN01: 7499111446; ROHS: Yes; Temp_Range: -40DegC to +85DegC
L16 = INDUCTOR: IND PWR 4.7uH@100kHz 1.2A 20% SMT; AGILE_PN: 180-78712; CAD_APPROVED: Yes; EN: 103-1-00086; HEIGHT: 1.8MM; MFG_NAME01: Taiyo Yuden; MFG_PN01: NR4018T4R7M; ROHS: Yes; TOL: 20%
R147 R168 = RES: RES MF 2.37K  1/10W 1% AEC-Q200 0402; AGILE_PN: 470-81584; CAD_APPROVED: Yes; EN: 101-1-00329; FPLIST: RC0402_25,RC0402_HD,0402_CC; HEIGHT: 0.40 MM; MFG_NAME01: KOA SPEER; MFG_PN01: RK73H1ETTP2371F; ROHS: Yes; TOL: 1%; Temp_Range: -55C to +155C; Tolerance: 1%
R148 = RES: RES MF 68K 1/16W 5% 0402; AGILE_PN: 470-30330; CAD_APPROVED: Yes; EN: 101-1-02813; FPLIST: RC0402_25,RC0402_HD,0402_CC; HEIGHT: 0.4MM; MFG_NAME01: TYCO ELECTRONICS; MFG_PN01: CRG0402J68K; ROHS: Yes; TOL: 5%; Tolerance: 5%
R173 = RES: RES MF 1.00k Ohm 1/16W 1% AEC-Q200 0402; AGILE_PN: 470-80511; CAD_APPROVED: Yes; EN: 101-1-00293; FPLIST: RC0402_25,RC0402_HD,0402_CC; HEIGHT: 0.4 MM; MFG_NAME01: KOA SPEER; MFG_PN01: RK73H1ETTP1001F; ROHS: Yes; TOL: 1%; Tolerance: 1%
R318 R319 = RES: RES MF 1.5K 1/16W 1% 0402; AGILE_PN: 470-80487; CAD_APPROVED: Yes; EN: 101-1-00310; FPLIST: RC0402_25,RC0402_HD,0402_CC; HEIGHT: 0.4MM; MFG_NAME01: BOURNS; MFG_PN01: CR0402-FX-1501GLF; ROHS: Yes; TOL: 1%; Tolerance: 1%
R373 R374 = RES: RES MF 270 OHM 1/16W 5% 0402; AGILE_PN: 470-30332; CAD_APPROVED: Yes; EN: 101-1-02755; FPLIST: RC0402_25,RC0402_HD,0402_CC; HEIGHT: 0.40 MM; MFG_NAME01: VISHAY INTERTECHNOLOGY; MFG_PN01: CRCW0402270RJNED; ROHS: Yes; TOL: 5%; Tolerance: 5%
U15 = PIMX8QM6AVUFFAB_BGA1313: IC CPU QUADMAX 2xA72 1.6GHz 4xA53 1.2GHZ M4 264MHZ FCPBGA1313; AGILE_PN: 330-77094; CAD_APPROVED: Yes; HEIGHT: 2.52MM; MFG_NAME01: NXP SEMICONDUCTORS; ROHS: Yes; Temp Range: -40°C to 125°C
U30 = AR8031_QFN48: IC XCVR ETHERNET PHY 10/100/1000G-BIT 3.3V QFN48; AGILE_PN: 312-80222; CAD_APPROVED: Yes; EN: 301-5-00025; HEIGHT: 0.8MM; MFG_NAME01: QUALCOMM ATHEROS, INC; MFG_PN01: AR8031-AL1B; ROHS: Yes
U48 = NTS0104PW_14P: IC VXLTR XCVR 4CH 1.65-3.6V/2.3-5.5V TSSOP14; AGILE_PN: 312-81228; CAD_APPROVED: Yes; EN: 301-0-01515; HEIGHT: 1.1MM; MFG_NAME01: NXP SEMICONDUCTORS; MFG_PN01: NTS0104PW,118; ROHS: Yes
X3 = XTAL_13: XTAL 25MHz 13PF 5x3.2mm SMT; AGILE_PN: 230-78201; CAD_APPROVED: Yes; EN: 108-1-00013; HEIGHT: 1MM; MFG_NAME01: CTS; MFG_PN01: 405C35B25M00000; ROHS: Yes; Temp_Range: -20C to +70C

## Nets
5V_SRC_ILIM: Q10.5(G2) R370.2 U37.6(ILIM_5V_VBUS)
GND: C89.2 C102.2 C105.2 C107.2 C113.2 C114.2 C119.2 C133.1 C177.2 C210.2 C217.2 C218.2 C219.2 C231.2 C232.2 C237.2 C238.1 C437.2 C455.2 C468.2 C488.2 C489.2 C503.2 C504.2 C509.2 C510.2 C511.2 C512.2 C513.2 C514.2 C515.2 C516.2 C517.2 C518.2 C520.2 C522.2 C525.2 C526.2 C527.2 C528.2 C531.2 C536.2 C537.2 C540.2 C541.2 C542.2 C543.1 C545.2 C547.2 C549.2 C552.2 D16.C(CATHODE) D30.A J13.1(GND) J13.4(GND) J13.7(GND) J14.12 J14.13 J17.A1(GND1) J17.A12(GND2) J17.B1(GND3) J17.B12(GND4) P1.A P2.A Q10.1(S1) Q10.4(S2) R122.2 R145.1 R150.2 R153.2 R156.2 R161.2 R164.2 R168.1 R170.2 R172.2 R175.2 R184.1 R285.1 R286.2 R287.2 R288.2 R304.1 R308.1 R309.1 R312.1 R314.1 R315.1 R317.1 R367.1 R368.1 R370.1 R372.1 R376.1 R387.2 R1477.2 R1478.2 U24.3(GND) U26.2(NC) U26.3(VSS1) U26.4(VSS2) U26.10(NC) U26.12(NC) U26.13(VSS3) U26.14(VSS4) U26.17(NC) U26.18(NC) U26.20(NC) U26.21(EP) U28.3(GND) U30.49(GND) U33.3(GND1) U33.8(GND2) U34.3(GND1) U34.8(GND2) U36.11(VSS) U36.17(EPAD) U37.17(GND) U38.3(GND1) U38.8(GND2) U48.7(GND) U54.C3(GND1) U54.D3(GND2) U54.E3(GND3) U55.3(GND1) U55.8(GND2) U56.3(GND1) U56.8(GND2) U58.B3(GND1) U58.C3(GND2) U58.D3(GND3) U59.3(GND) X3.2 X3.4 ; also on sheet 2 5 6 10 11 12 13 14 16 17 18 19 20 21 25 26 27 28 29 30 31 32
GND_EARTH: C537.1 J14.10(GND) J14.SH1 J14.SH2 R367.2
GND_USB3: J17.G1 J17.G2 J17.G3 J17.G4 J17.G5 J17.G6 J17.G7 R376.2
VCC_1V8: R144.1 R359.1 ; also on sheet 2 6 10 11 12 15 16 17 18 19 21 27 28 31
VCC_3V3: C89.1 C107.1 C113.1 C232.1 C437.1 C488.1 C489.1 C509.1 C518.1 C527.1 C528.1 C552.1 D12.C FB1.1 FB6.1 FB7.1 R126.2 R129.2 R143.2 R148.2 R189.1 R190.2 R289.1 R290.2 R297.2 R299.1 R318.1 R319.1 R365.2 U24.5(VCC) U28.5(VCC) U30.4(VDD33) U37.3(VDD) U48.1(VCCA) U48.8(OE) U48.14(VCCB) U59.5(VCC) ; also on sheet 6 10 12 18 20 25 27 28 31
VCC_12V0: C540.1 C541.1 R366.1 R386.2 U54.B2(VBUS1) U54.C2(VBUS2) U54.D2(VBUS3) U54.E1(VBUS4) U54.E2(VBUS5) ; also on sheet 2 5 10 29 30
VCC_CBT_3V3: C525.1 C526.1 FB7.2 U36.4(VDD)
VCC_ENET0_1V8: C510.1 C512.1 R149.2 R152.2 R155.2 R160.2 R163.2 R169.2 U30.29(VDDIO_REG) ; also on sheet 12
VCC_ETH_1V1: C114.1 C119.1 C133.2 FB2.2 L16.2 R147.2 U30.47(DVDDL)
VCC_PCIE_1V8: C406.2 C409.2 C418.2 ; also on sheet 12 25
VCC_PER_5V0: C238.2 C542.1 C543.2 R307.1 U37.12(VCONN_IN) U58.A1(VIN1) U58.A2(VIN2) ; also on sheet 2 5 6 25 27 29 30
VCC_VBUS: C237.1 C531.1 C536.1 C545.1 C547.1 D30.C D36.C J17.A4(VBUS1) J17.A9(VBUS2) J17.B4(VBUS3) J17.B9(VBUS) U37.15(VBUS) U54.A1(VINT1) U54.B1(VINT2) U54.C1(VINT3) U54.D1(VINT4) U58.C2(VBUS3) U58.D1(VBUS1) U58.D2(VBUS2)
VDDH_ETH_2V5: C513.1 R177.2 U30.10(VDDH_REG)
ATH_AVDD33: C516.1 C517.1 FB6.2 U30.16(AVDD33)
ATH_AVDDL: C503.1 C511.1 C514.1 C515.1 FB2.1 U30.8(AVDDL1) U30.13(AVDDL3) U30.19(AVDDL4) U30.44(AVDDL2)
ATH_LX: L16.1 U30.3(LX)
BB_ARD_MIK_RST_B: U15.B10(ENET0_REFCLK_125M_25M) ; also on sheet 2
BB_ENET1_MDC: U48.2(A1) ; also on sheet 2
BB_ENET1_MDIO: R319.2 U48.3(A2) ; also on sheet 2
BB_ENET1_RGMII_RX_CTL: U15.E49(ENET1_RGMII_RX_CTL) ; also on sheet 2
BB_ENET1_RGMII_RXC: U15.B50(ENET1_RGMII_RXC) ; also on sheet 2
BB_ENET1_RGMII_RXD0: U15.E51(ENET1_RGMII_RXD0) ; also on sheet 2
BB_ENET1_RGMII_RXD1: U15.C51(ENET1_RGMII_RXD1) ; also on sheet 2
BB_ENET1_RGMII_RXD2: U15.D52(ENET1_RGMII_RXD2) ; also on sheet 2
BB_ENET1_RGMII_RXD3: U15.E53(ENET1_RGMII_RXD3) ; also on sheet 2
BB_PCIE_CTRL1_CLKREQ_B: R125.2 R143.1 U15.A25(PCIE_CTRL1_CLKREQ_B) U28.2(A) ; also on sheet 2
BB_PCIE_CTRL1_PERST_B: U15.G25(PCIE_CTRL1_PERST_B) ; also on sheet 2
BB_PCIE_CTRL1_WAKE_B: U15.A27(PCIE_CTRL1_WAKE_B) ; also on sheet 2
BB_PCIE_RFCLK100M_PCIe_N: R142.2 R317.2 ; also on sheet 2
BB_PCIE_RFCLK100M_PCIe_P: R141.2 R315.2 ; also on sheet 2
BB_PCIE_RX0_N: U15.B22(PCIE1_RX0_N) ; also on sheet 2
BB_PCIE_RX0_P: U15.A21(PCIE1_RX0_P) ; also on sheet 2
BB_PCIE_TX0_N: C78.2 ; also on sheet 2
BB_PCIE_TX0_P: C79.2 ; also on sheet 2
BB_USB_OTG1_DN: R117.2 ; also on sheet 2
BB_USB_OTG1_DP: R116.2 ; also on sheet 2
BB_USB_OTG1_ID: R127.1 ; also on sheet 2
BB_USB_OTG1_PWR_ON: U15.J9(USB_SS3_TC0) ; also on sheet 2
BT_WAKE(USB_SS3_TC2): U15.F8(USB_SS3_TC2) ; also on sheet 26
BYP_ADD: C231.1 R183.1 U37.4(BYPASS)
CBTL_EN: U59.2(A) ; also on sheet 19
CBTL_EN_B: U36.3(XSD) U59.4(Y)
CPU_PER_RST_3V3: D11.C ; also on sheet 28 31
ENET0_INT_B: R358.2 ; also on sheet 15
ENET0_MDC: R151.1 U15.A9(ENET0_MDC) U48.13(B1)
ENET0_MDIO: R318.2 R345.1 U15.D10(ENET0_MDIO) U48.12(B2)
ENET1_REFCLK: U15.A11(ENET1_REFCLK_125M_25M) ; also on sheet 2
ENET1_RGMII_TX_CTL: U15.B48(ENET1_RGMII_TX_CTL) ; also on sheet 31
ENET1_RGMII_TXC: U15.D46(ENET1_RGMII_TXC) ; also on sheet 31
ENET1_RGMII_TXD0: U15.A49(ENET1_RGMII_TXD0) ; also on sheet 31
ENET1_RGMII_TXD1: U15.C47(ENET1_RGMII_TXD1) ; also on sheet 31
ENET1_RGMII_TXD2: U15.G47(ENET1_RGMII_TXD2) ; also on sheet 31
ENET1_RGMII_TXD3: U15.D48(ENET1_RGMII_TXD3) ; also on sheet 31
ENET_PHY_RST_B: C504.1 D11.A D12.A R148.1 U30.2(~{RST})
ETH0_RGMII_RX_CTL: R152.1 R153.1 U15.E43(ENET0_RGMII_RX_CTL) U30.32(RX_DV)
ETH0_RGMII_RXC: R149.1 R150.1 U15.B44(ENET0_RGMII_RXC) U30.33(RX_CLK)
ETH0_RGMII_RXD0: R155.1 R156.1 U15.A47(ENET0_RGMII_RXD0) U30.31(RXD0)
ETH0_RGMII_RXD1: R160.1 R161.1 U15.D44(ENET0_RGMII_RXD1) U30.30(RXD1)
ETH0_RGMII_RXD2: R163.1 R164.1 U15.C45(ENET0_RGMII_RXD2) U30.28(RXD2)
ETH0_RGMII_RXD3: R169.1 R170.1 U15.E45(ENET0_RGMII_RXD3) U30.27(RXD3)
ETH0_RGMII_TX_CTL: U15.E41(ENET0_RGMII_TX_CTL) U30.34(TX_EN)
ETH0_RGMII_TXC: U15.A41(ENET0_RGMII_TXC) U30.35(GTX_CLK)
ETH0_RGMII_TXD0: U15.A43(ENET0_RGMII_TXD0) U30.36(TXD0)
ETH0_RGMII_TXD1: U15.B42(ENET0_RGMII_TXD1) U30.37(TXD1)
ETH0_RGMII_TXD2: U15.A45(ENET0_RGMII_TXD2) U30.38(TXD2)
ETH0_RGMII_TXD3: U15.D42(ENET0_RGMII_TXD3) U30.39(TXD3)
ETH_CLKOUT: TP75.1(Pin1) U30.25(CLK_25M)
ETH_CT: C520.1 C522.1 J14.1(CT)
ETH_INT: R358.1 R359.2 U30.5(INT)
ETH_LED_1G_B: C219.1 R172.1 R173.2 U30.24(LED_LINK1000)
ETH_LED_10/100_B: C217.1 R373.2 U30.26(LED_LINK10_100)
ETH_LED_ACT_B: C218.1 R175.1 R177.1 R374.2 U30.23(LED_ACT)
ETH_PPS: TP79.1(Pin1) U30.22(PPS)
ETH_TRX0_N: J14.3(TRD1-) U30.12(TRXN0) U34.2(CH2) U34.9(NC3)
ETH_TRX0_P: J14.2(TRD1+) U30.11(TRXP0) U34.1(CH1) U34.10(NC4)
ETH_TRX1_N: J14.5(TRD2-) U30.15(TRXN1) U34.5(CH4) U34.6(NC1)
ETH_TRX1_P: J14.4(TRD2+) U30.14(TRXP1) U34.4(CH3) U34.7(NC2)
ETH_TRX2_N: J14.7(TRD3-) U30.18(TRXN2) U33.2(CH2) U33.9(NC3)
ETH_TRX2_P: J14.6(TRD3+) U30.17(TRXP2) U33.1(CH1) U33.10(NC4)
ETH_TRX3_N: J14.9(TRD4-) U30.21(TRXN3) U33.5(CH4) U33.6(NC1)
ETH_TRX3_P: J14.8(TRD4+) U30.20(TRXP3) U33.4(CH3) U33.7(NC2)
ETH_WOL: R144.2 TP56.1(Pin1) U30.40(WOL_INT)
I2C0_3V3_SCL: U37.8(I2C_SCL) ; also on sheet 25 28 31
I2C0_3V3_SDA: U37.7(I2C_SDA) ; also on sheet 25 28 31
I2C4_3V3_SCL: R290.1 U15.A13(ENET1_MDC) ; also on sheet 31
I2C4_3V3_SDA: R297.1 U15.C13(ENET1_MDIO) ; also on sheet 31
NAND_AIN: R125.1 R126.1 U24.2(A)
NAND_BIN: R128.1 R129.1 U24.1(B)
NX5P32_EN: U37.16(EN_SRC) U58.B4(EN)
NX5P32_FLT_B: R190.1 U37.11(FAULT_N) U58.A4(~{FLT})
NX5P32_FRS: U37.1(FRS_EN) U58.C4(FO)
NX5P32_ILIM: R368.2 R369.2 U58.A3(ILIM)
NX20P50_EN: Q10.2(G1) R372.2 U37.2(EN_SNK1)
NX20P_ACK: R365.1 U54.A2(ACK) ; also on sheet 19
NX20P_EN: Q10.6(D1) R366.2 U54.A3(\\~{E}N)
NX2050_OVLO: R386.1 R387.1 U54.B3(OVLO)
OSC_PCIE_CLK0_N: R142.1 U26.5(CLK0-)
OSC_PCIE_CLK0_P: R141.1 U26.6(CLK0+)
OSC_PCIE_CLK1_N: R139.1 U26.7(CLK1-)
OSC_PCIE_CLK1_P: R131.1 U26.8(CLK1+)
OSC_PCIE_CLK2_N: R130.1 U26.15(CLK2-)
OSC_PCIE_CLK2_P: R136.1 U26.16(CLK2+)
OTG1_ID: R122.1 R127.2 U15.A37(USB_OTG1_ID)
OTG1_VBUS: R304.2 R305.2 U15.A39(USB_OTG1_VBUS)
PCIE_CLK_OE1: U26.1(OE1) U28.4(Y)
PCIE_CLK_OE2: U24.4(Y) U26.11(OE2)
PCIE_CPU_REFCLK100M_N: R1474.2 U15.E25(PCIE_SATA_REFCLK100M_N)
PCIE_CPU_REFCLK100M_P: R1473.2 U15.F26(PCIE_SATA_REFCLK100M_P)
PCIE_GEN1_REFCLK100M_N: R139.2 R314.2 R1476.1
PCIE_GEN1_REFCLK100M_P: R131.2 R309.2 R1475.1
PCIE_GEN2_REFCLK100M_N: R130.2 R308.2 R1474.1
PCIE_GEN2_REFCLK100M_P: R136.2 R312.2 R1473.1
PCIE_OSC_PWR: C102.1 C105.1 C468.1 FB1.2 U26.9(VDD1) U26.19(VDD2)
PCIE_REF_C_CLK_N: R1474.3 R1476.3 R1478.1
PCIE_REF_C_CLK_P: R1473.3 R1475.3 R1477.1
PCIE_WIBT_CLKREQ_B: R128.2 U15.A17(PCIE_CTRL0_CLKREQ_B) ; also on sheet 26
PCIE_WIBT_CTRL0_PERST_B: U15.D20(PCIE_CTRL0_PERST_B) ; also on sheet 26
PCIE_WIBT_CTRL0_WAKE_B: U15.A15(PCIE_CTRL0_WAKE_B) ; also on sheet 26
PCIE_WIBT_REFCLK100M_N: R1476.2 ; also on sheet 26
PCIE_WIBT_REFCLK100M_P: R1475.2 ; also on sheet 26
PTN51_DBG_ACC: U15.L9(USB_SS3_TC1) U37.9(DBG_ACC)
PTN5110_ALERT_B: R189.2 U37.10(ALERT_N) ; also on sheet 19
RBIAS: R168.2 U30.9(RBIAS)
SATA0_RX0_N: C125.2 J13.5(RXn)
SATA0_RX0_P: C124.2 J13.6(RXp)
SATA0_TX0_N: C80.2 J13.3(TXn)
SATA0_TX0_P: C81.2 J13.2(TXp)
SATA_RX0_N: C125.1 U15.B20(PCIE_SATA0_RX0_N)
SATA_RX0_P: C124.1 U15.A19(PCIE_SATA0_RX0_P)
SATA_TX0_N: C80.1 U15.C17(PCIE_SATA0_TX0_N)
SATA_TX0_P: C81.1 U15.B16(PCIE_SATA0_TX0_P)
SLV_ADD: R183.2 R184.2 U37.5(SLV_ADDR)
SS_SBU1: J17.A8(SBU1) TP81.1(Pin1)
SS_SBU2: J17.B8(SBU2) TP82.1(Pin1)
SS_TX1_N: C236.2 J17.A3(TX1-) U38.4(CH3) U38.7(NC2)
SS_TX1_P: C235.2 J17.A2(TX1+) U38.5(CH4) U38.6(NC1)
SS_TX2_N: C535.2 J17.B3(TX2-) U55.4(CH3) U55.7(NC2)
SS_TX2_P: C534.2 J17.B2(TX2+) U55.5(CH4) U55.6(NC1)
TX0_N: C76.1 U15.C27(PCIE0_TX0_N)
TX0_P: C77.1 U15.B26(PCIE0_TX0_P)
TX1_N: C78.1 U15.C25(PCIE1_TX0_N)
TX1_P: C79.1 U15.B24(PCIE1_TX0_P)
USB2_DN: FL7.2 J17.A7(D1-) J17.B7(D-) U55.2(CH2) U55.9(NC3)
USB2_DP: FL7.3 J17.A6(D1+) J17.B6(D+) U55.1(CH1) U55.10(NC4)
USB3_CC1: J17.A5(CC1) P1.C U37.13(CC1)
USB3_CC2: J17.B5(CC2) P2.C U37.14(CC2)
USB3_MUX_RX_N: U15.B34(USB_SS3_RX_N) U36.14(A1_N)
USB3_MUX_RX_P: U15.C35(USB_SS3_RX_P) U36.13(A1_P)
USB3_MUX_TX_N: U15.B32(USB_SS3_TX_N) U36.9(A0_N)
USB3_MUX_TX_P: U15.A33(USB_SS3_TX_P) U36.10(A0_P)
USB3_RX1_N: J17.B10(RX1-) U36.1(B1_N) U56.5(CH4) U56.6(NC1)
USB3_RX1_P: J17.B11(RX1+) U36.2(B1_P) U56.4(CH3) U56.7(NC2)
USB3_RX2_N: J17.A10(RX2-) U36.16(C1_N) U38.2(CH2) U38.9(NC3)
USB3_RX2_P: J17.A11(RX2+) U36.15(C1_P) U38.1(CH1) U38.10(NC4)
USB3_SEL: U15.H10(USB_SS3_TC3) U36.12(SEL)
USB3_TX1_N: C236.1 U36.7(B0_N)
USB3_TX1_P: C235.1 U36.8(B0_P)
USB3_TX2_N: C535.1 U36.6(C0_N)
USB3_TX2_P: C534.1 U36.5(C0_P)
USB_HSIC0_DATA: TP48.1(Pin1) U15.H26(USB_HSIC0_DATA)
USB_HSIC0_STROBE: TP47.1(Pin1) U15.F28(USB_HSIC0_STROBE)
USB_OTG1_N: R117.1 R295.1 U15.C39(USB_OTG1_DN)
USB_OTG1_P: R116.1 R296.1 U15.B40(USB_OTG1_DP)
USB_OTG1_VBUS: C455.1 R305.1 R307.2 ; also on sheet 2
USB_OTG2_DN: FL7.1 U15.C37(USB_OTG2_DN)
USB_OTG2_DP: FL7.4 U15.B38(USB_OTG2_DP)
USB_OTG2_ID: R299.2 TP83.1(Pin1) U15.F30(USB_OTG2_ID)
USB_OTG2_VBUS: R285.2 R289.2 U15.A35(USB_OTG2_VBUS)
WIBT_PCIE0_RX0_N: U15.B30(PCIE0_RX0_N) ; also on sheet 26
WIBT_PCIE0_RX0_P: U15.A29(PCIE0_RX0_P) ; also on sheet 26
WIBT_PCIE0_TX0_N: C76.2 ; also on sheet 26
WIBT_PCIE0_TX0_P: C77.2 ; also on sheet 26
WIBT_USB_DN: R295.2 ; also on sheet 26
WIBT_USB_DP: R296.2 ; also on sheet 26
XTLI: C210.1 U30.7(XTLI) X3.1
XTLO: C177.1 U30.6(XTLO) X3.3
N1649673: C409.1 U15.M20(PCIE_SATA0_PHY_PLL_REF_RETURN)
N1649677: C406.1 U15.N23(PCIE1_PHY_PLL_REF_RETURN)
N1649695: C418.1 R279.2 U15.M28(PCIE0_PHY_PLL_REF_RETURN)
N1649713: R286.1 U15.E23(PCIE_REF_QR)
N1761422: R288.1 U15.E29(USB_OTG2_REXT)
N1761772: R287.1 U15.E27(USB_SS3_REXT)
N1814741: D16.A(ANODE) R173.1
N2173380: R279.1 U15.D22(PCIE_REXT)
N16508640: R345.2 U30.48(MDIO)
N16508666: R151.2 U30.1(MDC)
N16509426: R145.2 R147.1 U30.41(SD)
N16659116: D36.A U58.B1(VCP1) U58.B2(VCP2) U58.C1(VCP3)
N16659146: C549.1 U58.D4(CAP)
N18842703: J14.11 R374.1
N18842717: J14.14 R373.1
N18930378: Q10.3(D2) R369.1

Not connected (* = marked no-connect by the designer): U28 1(NC)*; U30 42(SON)* 43(SOP)* 45(SIN)* 46(SIP)*; U48 4(A3)* 5(A4)* 6(NC1)* 9(NC2)* 10(B4)* 11(B3)*; U56 1(CH1)* 2(CH2)* 9(NC3)* 10(NC4)*; U59 1(NC)*

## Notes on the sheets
sheet 22
- I/O VOLTAGE :3.3V
- USB 3.x Type C
- USB3.0 TYPE C CONNECTOR
- DIFFERENTIAL CHANNEL CROSSBAR SWITCH
- 5V,3.3A
   12V,3A
- 90-Ohm
  differential
  pairs
- CC LOGIC DETECTION
- OTG1 Can be connected to M.2 Connector
  or Baseboard USB2.0 port using these resistor options.
- 5V LOAD SWITCH
- I2C Address: "1010001x"
- 52.3K = 1.1A ILIM
  23.2K//52.3K = 3.3A ILIM
- I2C ADDRESS SELECTION
   SLV_ADDR PIN             ADDRESS
  =============================
   GND                       1010000x
   100K PULL UP TO BYPASS    1010011x
   UNCONNECTED               1010010x
   10K PULL UP TO BYPASS     1010001x
- 12V LOAD SWITCH
sheet 23
- PCIe & SATA
- SATA CONNECTOR
- I/O VOLTAGE :3.3V
- 100-Ohm
  differential
  pairs
- 85-Ohm
  differential
  pairs
- Single Lane to Base Board
- M.2 Connector on CPU Card has two PCIe Clock options:
  (Set resistor strapping as per table)
  1. Processor (NXP experimental use only; not recommended for customer use)
  2. External Clock generator (By default)
  M.2 Connector on Base Card has PCIe Clock
  Option only from External clock generator.
  (Set resistor strapping as per table)
- 100-Ohm
  differential
  pairs
- From Ext Osc U26
- PCIE_REXT
  845-Ohm  for  85-ohm differential impedance.
  909-Ohm  for  90-ohm differential impedance.
  1.02-kOhm for 100-ohm differential impedance.
- B2B CONNECTOR
- To M.2 Connector
- From Ext Osc U26
- Clock Source
- Option
  Resistors
- Clock
  Generator
- Processor
- R1473
- POS B
- POS A
- R1474
- POS B
- POS A
- PCIe CLOCK ENABLE LOGIC
- PCIe 100MHz OSCILLATOR
- R1475
- POS B
- POS A
- R1476
- POS B
- POS A
- M.2 Connector
  on CPU Card
- R128
- DNP
- MOUNT
- R129
- MOUNT
- DNP
- 100-Ohm
  differential
  pairs
- R130
- DNP
- MOUNT
- R131
- DNP
- MOUNT
- R136
- DNP
- MOUNT
- R139
- DNP
- MOUNT
- R1473
- NA
- POS A
- R1474
- NA
- POS A
- R1475
- NA
- POS A
- R1476
- NA
- POS A
- Mounted R143
- Mounted R275
- M.2 Connector
  on Base Card
- R128
- NA
- MOUNT
- DSC557 has internal 40kOhm pullup on OE1 and OE2.
  Default always ON for DSC557 Osc.
- R129
- NA
- DNP
- R130
- NA
- MOUNT
- R131
- NA
- MOUNT
- CLOCK CONFIG
  OE1         OE2          CLK0      CLK1     CLK2
  =================================================
   0           0           Hi-Z      Hi-Z     Hi-Z
   0           1           Hi-Z      EN       EN
   1           0           EN        Hi-Z     Hi-Z
   1           1           EN        EN       EN
- R136
- NA
- MOUNT
- R139
- NA
- MOUNT
sheet 24
- 1 Gbps ETHERNET PHY
- NOTE:
  Pull up resistor required to
  support open drain PHY MDIO pin,
  when PHY is outputting
  data. Pull up not required
  on MDC since line is
  only driven by i.MX8QM.
- 100-Ohm
  differential
  pairs
- B2B CONNECTOR
- 1 Gbps
- EMI Filter Reserved
- 470pF for LED
- ANA_MOD
- Select the core
  voltage level:
  0:1.1V, 1:1.2V
- PHYADDRESS2
- PHYADDRESS0
- PHYADDRESS1
- MODE[3]
- MODE[2]
- MODE[1]
- MODE[0]
- B2B CONNECTOR
- SEL_GPIO_INT
  Pin 5 mode:
  0: INT ; 1:GPIO
- MODE[3:0]
  (Default assemble: 0000)
  0000 1000 BaseT, RGMII;
  0001 1000 BaseT, SGMII;
  0010 1000X, RGMII, 50OHMS;
  0011 1000X, RGMII, 75OHMS;
  0100 1000X, TRANS, 50OHMS;
  0101 1000X, TRANS, 75OHMS;
  0110 100X, RGMII, 50OHMS;
  0111 100X, TRANS, 50OHMS;
  1100 BaseT, RMII1;
  1101 BaseT, RMII2;
  1110 100X, RGMII, 75OHMS;
  1111 100X, TRANS, 75OHMS;
  Others Reserved
- Isolation required due to
  MDIO interaction between
  certain PHYs & Switches
  per prior system bring-up.
  Users should evaluate their
  systems & eliminate if possible.
